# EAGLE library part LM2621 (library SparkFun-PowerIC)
Step-up switching regulator IC

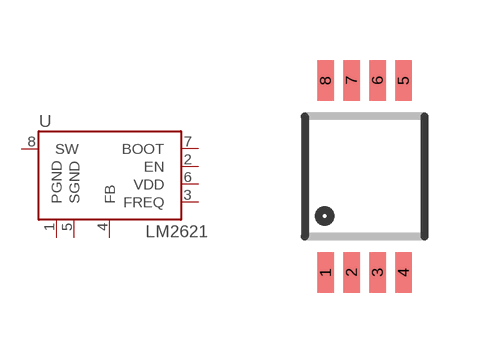
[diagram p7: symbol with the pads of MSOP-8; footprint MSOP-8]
Designator prefix -

## LM2621SMD  [MSOP-8]
1  PGND
2  EN
3  FREQ
4  FB
5  SGND
6  VDD
7  BOOT
8  SW

## Footprint MSOP-8 (pad centres in mm)
smd 0.41 x 1.02: 1 -0.975,-2.4; 2 -0.325,-2.4; 3 0.325,-2.4; 4 0.975,-2.4; 5 0.975,2.4; 6 0.325,2.4; 7 -0.325,2.4; 8 -0.975,2.4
